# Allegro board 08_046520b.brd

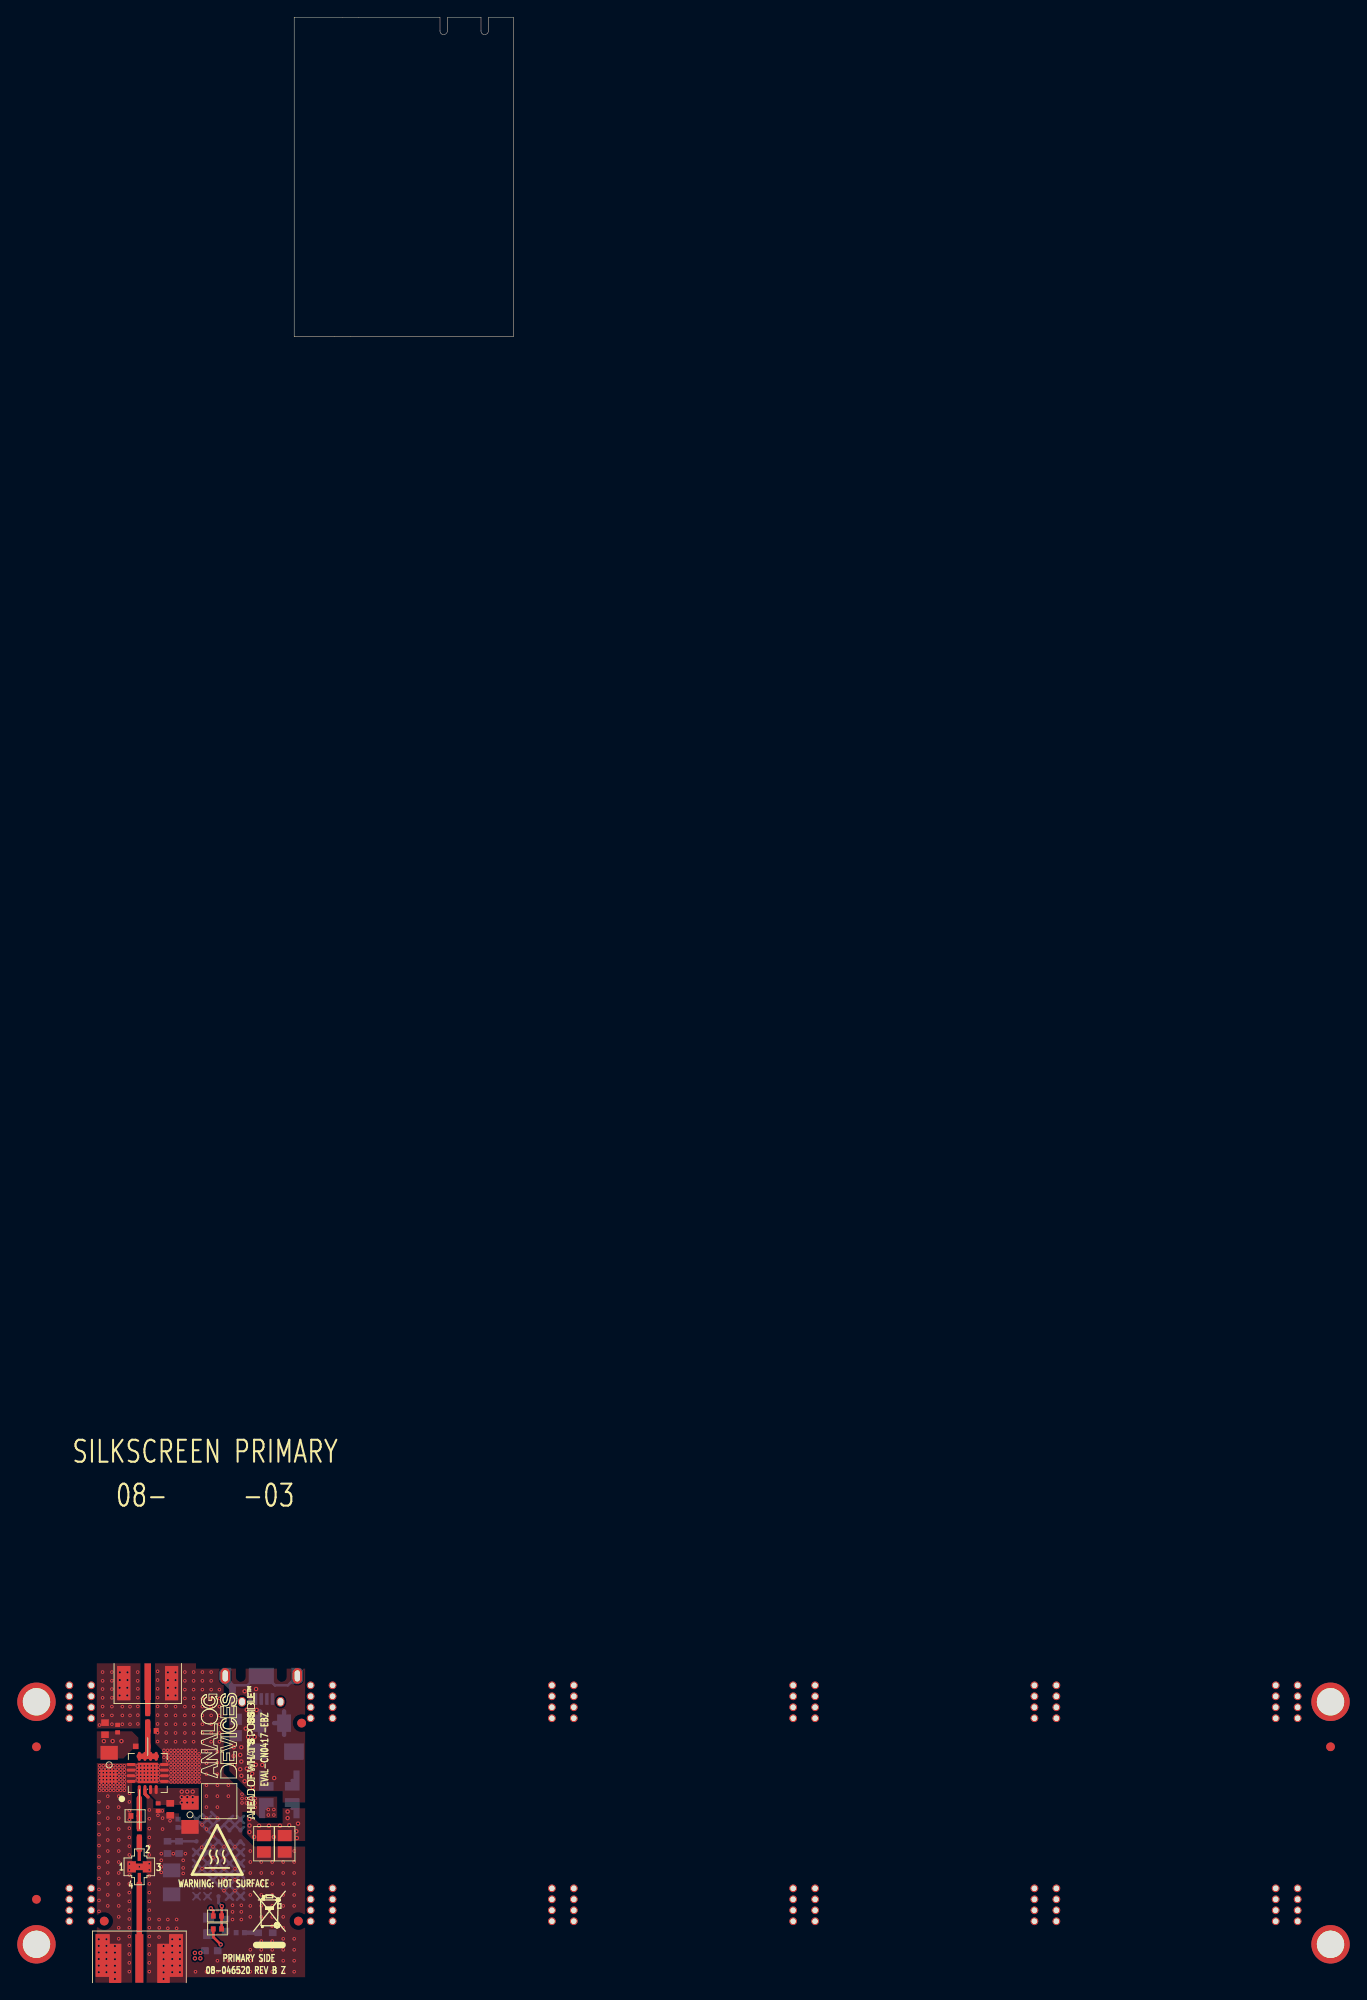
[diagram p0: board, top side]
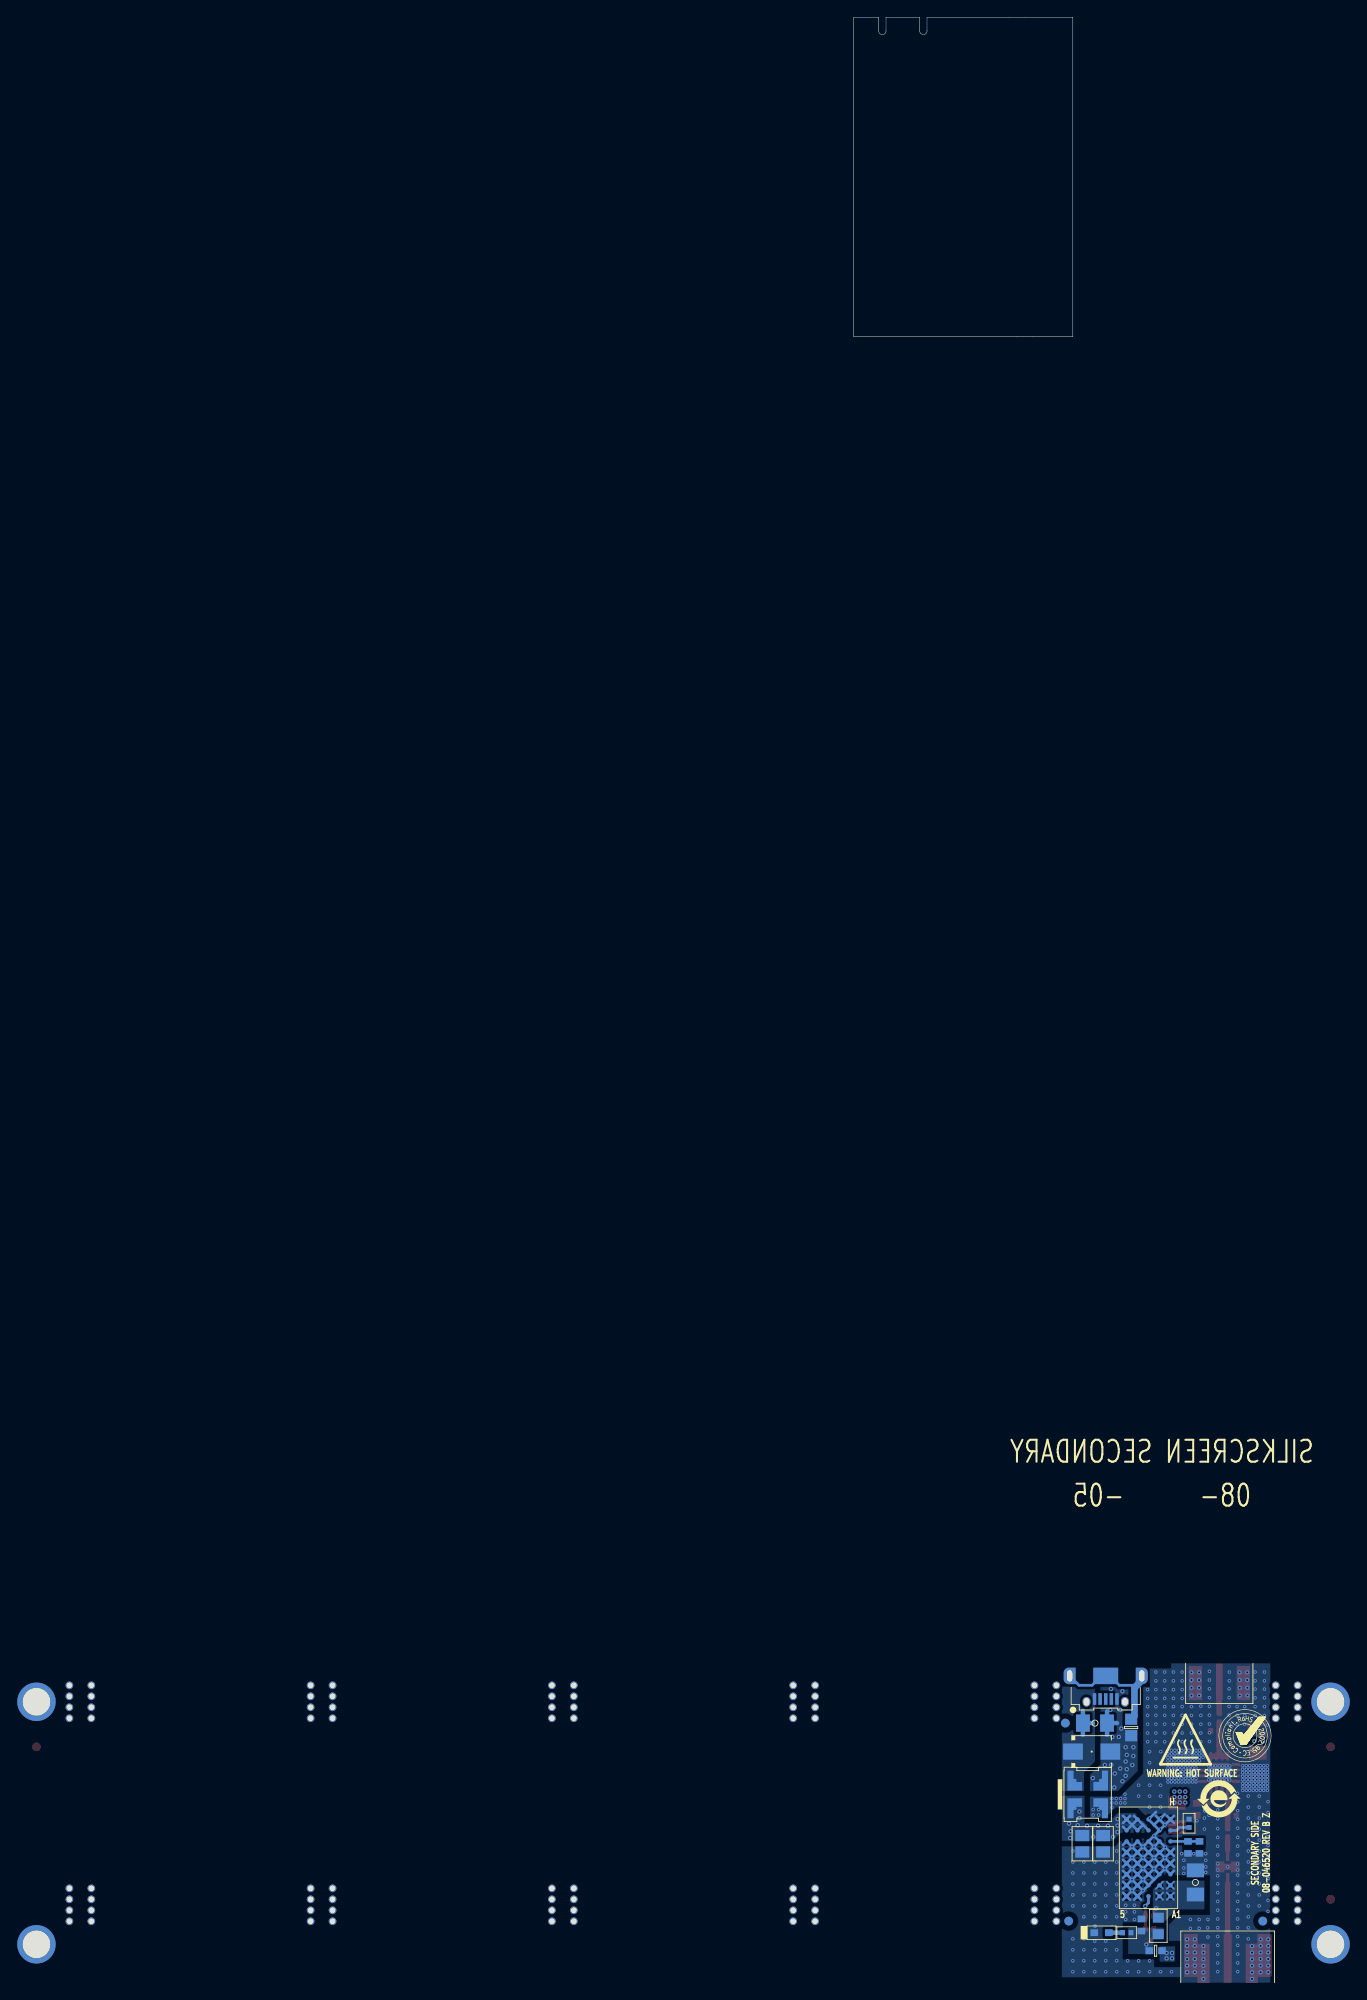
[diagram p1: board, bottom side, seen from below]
Outline 25.4 x 36.96 mm; copper layers: TOP, L2_GND, L3_PWR, BOTTOM. Coordinates in mm from the lower left corner of the outline.
Outline path: 0,36.96 16.88,36.96 16.88,35.38 arc(17.31,34.96) 17.74,35.38 17.74,36.96 21.63,36.96 21.63,35.38 arc(22.06,34.96) 22.49,35.38 22.49,36.96 25.4,36.96 25.4,0 0,0 0,36.96

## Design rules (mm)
constraint set DEFAULT: min track width 0.203
net group AMP: nets UNNAMED_7_ADL5606_I18_RFIN UNNAMED_7_ADL5606_I18_RFOUT1 UNNAMED_7_CAP_I75_N1 UNNAMED_7_CAP_I76_N2 UNNAMED_7_CNBNC5P_I149_CNTR UNNAMED_7_LINLTM8045_I104_FB

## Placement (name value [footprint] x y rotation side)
A1  ADL5606ACPZ  [QFN16_4X4_PAD2_36X2_36]  -16.96 -166.22 0 top
C1  20PF  [C0402#2]  -17.93 -173.16 90 top
C2  47UF  [C1206H71]  -2.57 -160.45 0 bottom
C3  4.7UF  [C0805H53]  -1.09 -174.42 90 bottom
C4  0.1UF  [C0805H53]  -3.51 -174.42 90 top
C5  0.1UF  [C0805H53]  -1.09 -174.42 90 top
C6  1UF  [C0603]  -13.33 -174.84 90 bottom
C7  0.1UF  [C0805H53]  -3.51 -174.42 90 bottom
C8  20PF  [C0402#2]  -16.96 -159.85 90 top
C9  1UF  [C0603]  -14.67 -174.84 90 bottom
C10  10UF  [C1206H71]  -12.06 -171.07 270 top
C11  0.01UF  [C0603]  -14.35 -170.43 270 top
C12  100pF  [C0402#2]  -15.75 -170.18 270 top
C13  10UF  [C1206H71]  -21.42 -165.29 270 top
C14  0.01UF  [C0603]  -21.91 -161.1 90 top
C15  100pF  [C0402#2]  -20.45 -161.1 90 top
C16  100uF  [C1206H71]  -14.2 -178.89 270 bottom
C17  1UF  [C0603]  -7.95 -183.82 270 bottom
CIN  2pF  [C0402]  -18.42 -171.2 0 top
COUT  3.3PF  [C0402]  -16.47 -161.35 180 top
D1  SMAJ5.0A-13-F  [DIOSMJ5_0]  -2.18 -163.76 180 bottom
DS1  LTST-C191KGKT  [LED0603_A]  -3.33 -184.71 180 bottom
E1  600OHM AT 100MEGHZ  [L0603]  -9.59 -186.8 180 bottom
FL1  2400-2500MEGHZ  [FL0805_A]  -17.93 -177.09 270 top
J1  132365-10  [CNSMARAL686W375H177]  -17.93 -190.5 270 top
J2  CON-SMA-EDGE-S  [CNSMARAL525W250H148]  -16.96 -153.54 90 top
L1  800OHMS AT 100MEGHZ  [L2020_A]  -1.73 -168.71 270 bottom
L2  18NH  [L7144A]  -17.66 -163.14 180 top
L3  1uH  [L0805]  -9.91 -183.92 270 bottom
NOREF  -  []  16.88 36.96 0 top
NOREF#2  -  []  21.63 36.96 0 top
NOREF#3  -  [unnamed#2]  57.78 -180.85 0 top
NOREF#4  -  [unnamed#2]  1.91 -179.58 0 top
NOREF#5  -  [unnamed#2]  1.91 -182.12 0 top
NOREF#6  -  [unnamed#2]  85.72 -156.08 0 top
NOREF#7  -  [unnamed#2]  -26.04 -156.08 0 top
NOREF#8  -  [unnamed#2]  29.84 -158.62 0 top
NOREF#9  -  [unnamed#2]  -23.49 -158.62 0 top
NOREF#10  -  []  22.49 36.96 0 top
NOREF#11  -  [unnamed#2]  32.38 -159.89 0 top
NOREF#12  -  [unnamed#2]  113.67 -180.85 0 top
NOREF#13  -  [unnamed#2]  116.2 -156.08 0 top
NOREF#14  -  []  177 11.95 0 top
NOREF#15  -  [unnamed#2]  85.72 -183.39 0 top
NOREF#16  -  [unnamed#2]  60.33 -182.12 0 top
NOREF#17  -  [unnamed#2]  57.78 -157.35 0 top
NOREF#18  -  [unnamed#2]  1.91 -159.89 0 top
NOREF#19  -  []  32.38 -190.5 0 top
NOREF#20  -  [unnamed#2]  116.2 -179.58 0 top
NOREF#21  -  []  -23.49 -190.5 0 top
NOREF#22  -  [unnamed#2]  88.27 -157.35 0 top
NOREF#23  -  [unnamed#2]  60.33 -179.58 0 top
NOREF#24  -  [unnamed#2]  85.72 -180.85 0 top
NOREF#25  -  [unnamed#2]  -29.84 -157.99 0 top
NOREF#26  -  [unnamed#2]  57.78 -159.89 0 top
NOREF#27  -  []  0 0 0 top
NOREF#28  -  [unnamed#2]  -29.84 -180.85 0 top
NOREF#29  -  [unnamed#2]  113.67 -158.62 0 top
NOREF#30  -  [unnamed#2]  -29.84 -186.06 0 top
NOREF#31  -  []  88.27 -190.5 0 top
NOREF#32  -  [unnamed#2]  60.33 -156.08 0 top
NOREF#33  -  []  85.72 -190.5 0 top
NOREF#34  -  [unnamed#2]  32.38 -183.39 0 top
NOREF#35  -  [unnamed#2]  85.72 -158.62 0 top
NOREF#36  -  [unnamed#2]  4.45 -158.62 0 top
NOREF#37  -  []  25.4 0 0 top
NOREF#38  -  [unnamed#2]  -23.49 -156.08 0 top
NOREF#39  -  []  -3.07 -186.45 0 top
NOREF#40  -  [unnamed#2]  88.27 -159.89 0 top
NOREF#41  -  [unnamed#2]  88.27 -158.62 0 top
NOREF#42  -  [unnamed#2]  0.48 -183.37 0 top
NOREF#43  -  [unnamed#2]  4.45 -179.58 0 top
NOREF#44  -  []  -33.66 -190.5 0 top
NOREF#45  -  [unnamed#2]  1.91 -157.35 0 top
NOREF#46  -  [unnamed#2]  120.02 -186.06 0 top
NOREF#47  -  [unnamed#2]  32.38 -180.85 0 top
NOREF#48  -  []  29.84 -190.5 0 top
NOREF#49  -  [unnamed#2]  -26.04 -182.12 0 top
NOREF#50  -  [unnamed#2]  85.72 -182.12 0 top
NOREF#51  -  []  1.5 7.13 0 top
NOREF#52  -  [unnamed#2]  113.67 -179.58 0 top
NOREF#53  -  [unnamed#2]  29.84 -182.12 0 top
NOREF#54  -  []  -108.74 -271.92 0 top
NOREF#55  -  []  -29.84 -186.06 0 top
NOREF#56  -  [unnamed#2]  60.33 -180.85 0 top
NOREF#57  -  []  -29.84 -186.06 0 top
NOREF#58  -  []  183.04 23.81 90 top
NOREF#59  -  []  9.05 -48.78 0 top
NOREF#60  -  [unnamed#2]  32.38 -182.12 0 top
NOREF#61  -  []  4.45 -190.5 0 top
NOREF#62  -  []  0 0 0 top
NOREF#63  -  []  1.91 -190.5 0 top
NOREF#64  -  []  113.67 -190.5 0 top
NOREF#65  -  [unnamed#2]  60.33 -157.35 0 top
NOREF#66  -  []  -5.08 -153.54 180 top
NOREF#67  -  [unnamed#2]  -26.04 -180.85 0 top
NOREF#68  -  [unnamed#2]  88.27 -180.85 0 top
NOREF#69  -  []  -33.66 -153.54 0 top
NOREF#70  -  []  116.2 -190.5 0 top
NOREF#71  -  []  16.47 33.39 0 top
NOREF#72  -  []  17.74 36.96 0 top
NOREF#73  -  [unnamed#2]  1.91 -158.62 0 top
NOREF#74  -  [unnamed#2]  88.27 -182.12 0 top
NOREF#75  -  [unnamed#2]  29.84 -159.89 0 top
NOREF#76  -  []  123.83 -190.5 0 top
NOREF#77  -  [unnamed#2]  4.45 -157.35 0 top
NOREF#78  -  [unnamed#2]  120.02 -157.99 0 top
NOREF#79  -  [unnamed#2]  1.91 -183.39 0 top
NOREF#80  -  [unnamed#2]  0.86 -160.45 0 top
NOREF#81  -  []  -27.23 -100.31 0 top
NOREF#82  -  []  187.79 -7.49 0 top
NOREF#83  -  [unnamed#2]  -26.04 -157.35 0 top
NOREF#84  -  [unnamed#2]  60.33 -183.39 0 top
NOREF#85  -  [unnamed#2]  113.67 -159.89 0 top
NOREF#86  -  [unnamed#2]  116.2 -180.85 0 top
NOREF#87  -  [unnamed#2]  57.78 -158.62 0 top
NOREF#88  -  [unnamed#2]  4.45 -180.85 0 top
NOREF#89  -  []  0 36.96 0 top
NOREF#90  -  []  177 26.12 0 top
NOREF#91  -  []  25.4 0 90 top
NOREF#92  -  [unnamed#2]  -23.49 -157.35 0 top
NOREF#93  -  [unnamed#2]  85.72 -157.35 0 top
NOREF#94  -  [unnamed#2]  57.78 -179.58 0 top
NOREF#95  -  []  165.98 23.84 0 top
NOREF#96  -  [unnamed#2]  88.27 -156.08 0 top
NOREF#97  -  [unnamed#2]  1.91 -156.08 0 top
NOREF#98  -  []  -108.74 -271.92 0 top
NOREF#99  -  [unnamed#2]  -23.49 -179.58 0 top
NOREF#100  -  []  -23.49 -190.5 0 top
NOREF#101  -  []  -33.66 -190.5 0 top
NOREF#102  -  [unnamed#2]  -23.49 -183.39 0 top
NOREF#103  -  [unnamed#2]  4.45 -156.08 0 top
NOREF#104  -  [unnamed#2]  32.38 -158.62 0 top
NOREF#105  -  [unnamed#2]  -26.04 -158.62 0 top
NOREF#106  -  [unnamed#2]  -26.04 -159.89 0 top
NOREF#107  -  [unnamed#2]  4.45 -159.89 0 top
NOREF#108  -  []  -92.88 125.68 0 top
NOREF#109  -  [unnamed#2]  29.84 -157.35 0 top
NOREF#110  -  []  57.78 -190.5 0 top
NOREF#111  -  [unnamed#2]  116.2 -157.35 0 top
NOREF#112  -  [unnamed#2]  32.38 -157.35 0 top
NOREF#113  -  [unnamed#2]  -22 -183.37 0 top
NOREF#114  -  []  174.64 -5.83 90 top
NOREF#115  -  [unnamed#2]  4.45 -182.12 0 top
NOREF#116  -  [unnamed#2]  116.2 -159.89 0 top
NOREF#117  -  [unnamed#2]  57.78 -183.39 0 top
NOREF#118  -  []  -50 17.88 0 top
NOREF#119  -  [unnamed#2]  88.27 -179.58 0 top
NOREF#120  -  [unnamed#2]  32.38 -156.08 0 top
NOREF#121  -  [unnamed#2]  85.72 -179.58 0 top
NOREF#122  -  []  28.1 -44.97 0 top
NOREF#123  -  []  0 36.96 0 top
NOREF#124  -  [unnamed#2]  1.91 -180.85 0 top
NOREF#125  -  [unnamed#2]  113.67 -182.12 0 top
NOREF#126  -  [unnamed#2]  4.45 -183.39 0 top
NOREF#127  -  [unnamed#2]  60.33 -159.89 0 top
NOREF#128  -  []  -26.04 -190.5 0 top
NOREF#129  -  [unnamed#2]  113.67 -157.35 0 top
NOREF#130  -  [unnamed#2]  29.84 -179.58 0 top
NOREF#131  -  [unnamed#2]  29.84 -156.08 0 top
NOREF#132  -  []  -23.49 -153.54 270 top
NOREF#133  -  []  171.17 -76.31 0 top
NOREF#134  -  [unnamed#2]  -23.49 -159.89 0 top
NOREF#135  -  []  179.36 29.73 90 top
NOREF#136  -  [unnamed#2]  29.84 -180.85 0 top
NOREF#137  -  []  -22.27 -162.95 0 top
NOREF#138  -  [unnamed#2]  60.33 -158.62 0 top
NOREF#139  -  [unnamed#2]  85.72 -159.89 0 top
NOREF#140  -  [unnamed#2]  -23.49 -182.12 0 top
NOREF#141  -  [unnamed#2]  57.78 -182.12 0 top
NOREF#142  -  [unnamed#2]  116.2 -182.12 0 top
NOREF#143  -  []  -108.74 -271.92 0 top
NOREF#144  -  [unnamed#2]  -26.04 -179.58 0 top
NOREF#145  -  []  60.33 -190.5 0 top
NOREF#146  -  [unnamed#2]  116.2 -158.62 0 top
NOREF#147  -  [unnamed#2]  29.84 -183.39 0 top
NOREF#148  -  [unnamed#2]  32.38 -179.58 0 top
NOREF#149  -  [unnamed#2]  -23.49 -180.85 0 top
NOREF#150  -  [unnamed#2]  116.2 -183.39 0 top
NOREF#151  -  [unnamed#2]  120.02 -163.19 0 top
NOREF#152  -  []  1.5 7.13 0 top
NOREF#153  -  [unnamed#2]  -29.84 -163.19 0 top
NOREF#154  -  []  -5.08 -190.5 90 top
NOREF#155  -  [unnamed#2]  113.67 -156.08 0 top
NOREF#156  -  [unnamed#2]  -26.04 -183.39 0 top
NOREF#157  -  []  165.98 -16.72 0 top
NOREF#158  -  []  -10.31 -135.27 0 top
NOREF#159  -  [unnamed#2]  113.67 -183.39 0 top
NOREF#160  -  [unnamed#2]  57.78 -156.08 0 top
NOREF#161  -  [unnamed#2]  88.27 -183.39 0 top
NOREF#162  -  [unnamed#2]  0.86 -160.45 180 bottom
NOREF#163  -  [unnamed#2]  -22 -183.37 180 bottom
NOREF#164  -  [unnamed#2]  0.48 -183.37 180 bottom
NOREF#165  -  []  -16.92 -169.22 180 bottom
P1  47590-0001  [CNMOLEX47590-0001]  -3.81 -153.54 270 bottom
R1  1K  [R0805]  -6.76 -160.96 90 bottom
R2  60.4K  [R0402]  -8.89 -182.78 180 top
R3  182K  [R0402]  -8.89 -184.28 180 top
R4  140  [R0402]  -6.25 -184.71 180 bottom
RT  115K  [R0402]  -13.46 -172.05 90 bottom
U1  LTM8045MPY#PBF  [BGA40]  -8.76 -176.05 90 bottom

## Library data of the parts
A1 = ADL5606: User Part Number: UPN; Tolerance: N/A; alternate symbols: (); part number: ADL5606_SM-ADL5606ACPZ,E026828,QFN16_4X4_PAD2_36X2_36; tolerance: N/A
C1 C8 = CAP: Tolerance: 5; User Part Number: UPN; alternate symbols: C0402L_ALT; part number: CAP_SM-20PF,50V,5,E033239,C0402; tolerance: 5
C2 = CAP: Tolerance: 20; User Part Number: UPN; alternate symbols: (); part number: CAP_SM-47UF,10V,20,E028092,C1206H71; tolerance: 20
C3 = CAP: Tolerance: 10; User Part Number: UPN; alternate symbols: (); part number: CAP_SM-4.7UF,25V,10,E025752,C0805H53; tolerance: 10
C4 C5 C7 = CAP: Tolerance: 10; User Part Number: UPN; alternate symbols: (); part number: CAP_SM-0.1UF,50V,10,E033336,C0805H53; tolerance: 10
C6 C9 C17 = CAP: Tolerance: 10; User Part Number: UPN; alternate symbols: C0603L_ALT; part number: CAP_SM-1UF,25V,10,E025743,C0603; tolerance: 10
C10 C13 = CAP: Tolerance: 10; User Part Number: UPN; alternate symbols: (); part number: CAP_SM-10UF,10V,10,E027443,C1206H71; tolerance: 10
C11 C14 = CAP: Tolerance: 10; User Part Number: UPN; alternate symbols: C0603L_ALT; part number: CAP_SM-0.01UF,100V,10,E032297,C0603; tolerance: 10
C12 C15 = CAP: Tolerance: 5; User Part Number: UPN; alternate symbols: C0402L_ALT; part number: CAP_SM-100PF,50V,5,E022402,C0402; tolerance: 5
C16 = CAP: Tolerance: 20; User Part Number: UPN; alternate symbols: (); part number: CAP_SM-100UF,6.3V,20,E016591,C1206H71; tolerance: 20
CIN = CAP: Tolerance: 0.25pF; User Part Number: UPN; alternate symbols: C0402L_ALT; part number: CAP_SM-2PF,50V,0.25PF,E012548,C0402; tolerance: 0.25pF
COUT = CAP: Tolerance: 0.1PF; User Part Number: UPN; alternate symbols: C0402L_ALT; part number: CAP_SM-3.3PF,50V,0.1PF,E027135,C0402; tolerance: 0.1PF
D1 = DIO: Tolerance: N/A; User Part Number: UPN; alternate symbols: (); part number: DIO_SM-SMAJ5.0A-13-F,5V,N/A,E001108,DIOSMJ5_0; tolerance: N/A
DS1 = DIOLED: User Part Number: UPN; Tolerance: N/A; alternate symbols: (); part number: DIOLED_SM-LTST-C191KGKT,2V,N/A,E033001,LED0603_A; tolerance: N/A
E1 = FERRITE: Tolerance: 25; User Part Number: UPN; alternate symbols: (); part number: FERRITE_SM-600OHM AT 100MEGHZ,25,E028908,L0603; tolerance: 25
FL1 = FLTRBP4P_V2: User Part Number: UPN; Tolerance: N/A; alternate symbols: (); part number: FLTRBP4P_V2_SM-2400-2500MEGHZ,E023131,FL0805_A; tolerance: N/A
J1 = CNBNC5P: alternate symbols: (CNSMARAL686W375H177_CNSMARAL535W256H152); part number: CNBNC5P_SM-132365-10,E033180,CNSMARAL686W375H177; tolerance: N/A
J2 = CNBNC5P: Tolerance: N/A; User Part Number: UPN; alternate symbols: (); part number: CNBNC5P_SM-CON-SMA-EDGE-S,E028678,CNSMARAL525W250H148; tolerance: N/A
L1 = CHOKE4P: User Part Number: UPN; Tolerance: N/A; alternate symbols: (); part number: CHOKE4P_SM-800OHMS AT 100MEGHZ,N/A,E027130,L2020_A; tolerance: N/A
L2 = IND: Tolerance: 5; User Part Number: UPN; alternate symbols: (); part number: IND_SM-18NH,5,E029275,L7144A; tolerance: 5
L3 = IND: Tolerance: 20; User Part Number: UPN; alternate symbols: (L0805L); part number: IND_SM-1UH,20,E010399,L0805; tolerance: 20
P1 = CN5P_3SHLD: User Part Number: UPN; Tolerance: N/A; alternate symbols: (); part number: CN5P_3SHLD_SM-47590-0001,E015753,CNMOLEX47590-0001; tolerance: N/A
R1 = RES: Tolerance: 1; User Part Number: UPN; alternate symbols: (R0805L); part number: RES_SM-1K,E023448,1/3W,1,R0805; tolerance: 1
R2 = RES: Tolerance: 1; User Part Number: UPN; alternate symbols: (R0402L); part number: RES_SM-60.4K,E022436,1/10W,1,R0402; tolerance: 1
R3 = RES: Tolerance: 1; User Part Number: UPN; alternate symbols: (R0402L); part number: RES_SM-182K,E025180,1/10W,1,R0402; tolerance: 1
R4 = RES: Tolerance: 1; User Part Number: UPN; alternate symbols: (R0402L); part number: RES_SM-140,E006740,1/16W,1,R0402; tolerance: 1
RT = RES: Tolerance: 1; User Part Number: UPN; alternate symbols: (R0402L); part number: RES_SM-115K,E025179,1/10W,1,R0402; tolerance: 1
U1 = LINLTM8045: Tolerance: N/A; User Part Number: UPN; alternate symbols: (); part number: LINLTM8045_SM-LTM8045MPY#PBF,E028897,BGA40; tolerance: N/A

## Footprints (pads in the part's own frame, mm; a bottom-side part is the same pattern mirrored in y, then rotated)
BGA40
  round 0.508 smd: A1(-4.445,-2.54) A2(-4.445,-1.27) A3(-4.445,0) A4(-4.445,1.27) A5(-4.445,2.54) B1(-3.175,-2.54) B2(-3.175,-1.27) B3(-3.175,0) B4(-3.175,1.27) B5(-3.175,2.54) C1(-1.905,-2.54) C2(-1.905,-1.27) C3(-1.905,0) C4(-1.905,1.27) C5(-1.905,2.54) D1(-0.635,-2.54) D2(-0.635,-1.27) D3(-0.635,0) D4(-0.635,1.27) D5(-0.635,2.54) E1(0.635,-2.54) E2(0.635,-1.27) E3(0.635,0) E4(0.635,1.27) E5(0.635,2.54) F1(1.905,-2.54) F2(1.905,-1.27) F3(1.905,0) F4(1.905,1.27) F5(1.905,2.54) G1(3.175,-2.54) G2(3.175,-1.27) G3(3.175,0) G4(3.175,1.27) G5(3.175,2.54) H1(4.445,-2.54) H2(4.445,-1.27) H3(4.445,0) H4(4.445,1.27) H5(4.445,2.54)
C0402
  rect 0.584x0.66 smd: 1(-0.49,0) 2(0.49,0)
C0402#2
  rect 0.483x0.559 smd: 1(-0.438,0) 2(0.438,0)
C0603
  rect 0.762x0.889 smd: 1(-0.699,0) 2(0.699,0)
C0805H53
  rect 1.295x1.6 smd: 1(-0.953,0) 2(0.953,0)
C1206H71
  rect 1.6x2.007 smd: 1(-1.397,0) 2(1.397,0)
CNMOLEX47590-0001
  oval 1.118x0.914 hole 0.864x0.66: (4.45,-2.225) (4.45,2.225)
  rect 1.346x0.406 smd: 1(4.123,-1.3) 2(4.123,-0.65) 3(4.123,0) 4(4.123,0.65) 5(4.123,1.3)
  oval 1.803x1.118 hole 1.295x0.61: SH1(1.45,4.175) SH3(1.45,-4.175)
  rect 1.905x2.896 smd: SH2(1.45,0)
CNSMARAL525W250H148
  rect 4.242x0.762 smd: 1(-2.121,0)
  rect 3.962x1.499 smd: 2(-2.281,2.77) 3(-2.281,2.77) 4(-2.281,-2.77) 5(-2.281,-2.77)
CNSMARAL686W375H177
  rect 5.613x0.94 smd: 1(-2.807,0)
  custom 0.737x0.737 smd: 2(-2.801,3.576) 3(-2.801,-3.576) 4(-2.801,3.576) 5(-2.801,-3.576)
DIOSMJ5_0
  rect 2.286x1.88 smd: A(2.164,0) C(-2.164,0)
FL0805_A
  rect 1.295x0.991 smd: 1(0,-0.895) 3(0,0.895)
  rect 0.991x0.356 smd: 2(-1.195,0) 4(1.195,0)
L0603
  rect 0.889x0.813 smd: 1(-0.737,0) 2(0.737,0)
L0805
  rect 1.143x1.27 smd: 1(-0.953,0) 2(0.953,0)
L2020_A
  custom 0.425x0.425 smd: 1(-1.606,-1.501) 2(1.606,-1.501) 3(1.606,1.501) 4(-1.606,1.501)
L7144A
  rect 0.635x0.635 smd: 1(-0.699,0) 2(0.699,0)
LED0603_A
  rect 0.889x0.787 smd: A(0.845,0) C(-0.845,0)
QFN16_4X4_PAD2_36X2_36
  oval 0.356x1.041 smd: 1(-0.975,-1.925) 2(-0.325,-1.925) 3(0.325,-1.925) 4(0.975,-1.925) 9(0.975,1.925) 10(0.325,1.925) 11(-0.325,1.925) 12(-0.975,1.925)
  oval 1.041x0.356 smd: 5(1.925,-0.975) 6(1.925,-0.325) 7(1.925,0.325) 8(1.925,0.975) 13(-1.925,0.975) 14(-1.925,0.325) 15(-1.925,-0.325) 16(-1.925,-0.975)
  rect 2.362x2.362 smd: PAD(0,0)
R0402
  rect 0.559x0.61 smd: 1(-0.483,0) 2(0.483,0)
R0805
  rect 1.295x1.397 smd: 1(-0.953,0) 2(0.953,0)
unnamed#2
  round 0.889 hole 0.635 unplated: (0,0)

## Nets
5V: A1.3(VCC) A1.4 C10.1 C11.1 C12.1 C13.1 C14.1 C15.1 E1.2(N2) L2.2(N2)
GND: A1.2 A1.5 A1.6 A1.7 A1.8 A1.13 A1.14 A1.15 A1.16 A1.PAD C3.1 C4.1 C5.1 C6.1 C7.1 C9.1 C10.2(N2) C11.2(N2) C12.2(N2) C13.2(N2) C14.2(N2) C15.2(N2) C16.1 C17.1 CIN.1 COUT.1 DS1.C FL1.1 FL1.3 J1.2 J1.3 J1.4 J1.5(SH4) J2.2 J2.3 J2.4 J2.5(SH4) L1.3 RT.2(N2) U1.A4 U1.A5 U1.B3 U1.B4 U1.B5(VOUT-_4) U1.C1 U1.C2 U1.C3 U1.C4 U1.C5 U1.D1 U1.D2 U1.D3 U1.D4 U1.D5 U1.E1 U1.E2 U1.E3 U1.E4 U1.E5 U1.F2 U1.F3 U1.F4 U1.F5 U1.G2 U1.H1 U1.H2 U1.H3
PGND: C2.1 D1.A(P) L1.4(N4) P1.5 R1.1
UNNAMED_7_ADL5606_I18_RFIN: A1.1 C1.2(N2) CIN.2(N2)
UNNAMED_7_ADL5606_I18_RFOUT1: A1.9 A1.10 A1.11 A1.12 C8.1 COUT.2(N2) L2.1
UNNAMED_7_CAP_I75_N1: C1.1 FL1.2(OUT)
UNNAMED_7_CAP_I76_N2: C8.2(N2) J2.1
UNNAMED_7_CAP_I108_N2: C16.2(N2) L3.1 R2.2(N2) U1.A1 U1.A2 U1.B1 U1.B2
UNNAMED_7_CAP_I113_N2: C3.2(N2) C4.2(N2) C5.2(N2) C7.2(N2) L1.2 U1.G3 U1.G4 U1.G5 U1.H4 U1.H5
UNNAMED_7_CAP_I120_N2: C2.2(N2) D1.C L1.1 P1.1
UNNAMED_7_CAP_I132_N2: C6.2(N2) C9.2(N2) U1.F1
UNNAMED_7_CN5P3SHLD_I127_N6: P1.SH1 P1.SH2 P1.SH3(N8) R1.2(N2)
UNNAMED_7_CNBNC5P_I149_CNTR: FL1.4 J1.1
UNNAMED_7_DIOLED_I150_P: DS1.A(P) R4.1
UNNAMED_7_FERRITE_I107_N1: C17.2(N2) E1.1 L3.2(N2) R3.2(N2) R4.2(N2)
UNNAMED_7_LINLTM8045_I104_FB: R2.1 R3.1 U1.A3
UNNAMED_7_LINLTM8045_I104_RT: RT.1 U1.G1

Pads without a net: P1 2 3 4

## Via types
v1: diameter 0.508, hole 0.254, TOP to BOTTOM, 107 vias
v2: diameter 0.406, hole 0.203, TOP to BOTTOM, 499 vias

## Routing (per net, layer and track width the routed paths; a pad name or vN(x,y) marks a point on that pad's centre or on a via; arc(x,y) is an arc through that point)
5V:
  vias: v1(-22.04,-162.54) v1(-21.02,-162.54) v1(-20.01,-162.54) v1(-13.02,-168.38) v1(-13.02,-169.02) v1(-13.02,-169.65) v1(-12.39,-168.38) v1(-12.39,-169.02) v1(-12.39,-169.65) v1(-11.75,-168.38) v1(-11.75,-169.02) v1(-11.75,-169.65) v1(-11.5,-187.05) v1(-11.5,-187.69) v1(-10.86,-187.05) v1(-10.86,-187.69)
GND: length 82.9
  TOP w0.356: A1.2 -17.28,-168.65 -17.24,-168.69
  TOP w0.381: -16.92,-169.02 -17.24,-168.69
  BOTTOM w0.305: U1.H2 -10.64,-171 ; U1.H2 -9.4,-172.24 ; U1.H2 v2(-10.67,-172.24) ; U1.H2 -9.62,-171.19 ; U1.A4 v2(-8.13,-179.86) ; U1.A4 v2(-6.86,-179.86) ; U1.A4 -7.08,-180.9 ; U1.A4 -7.9,-180.9 ; v2(-8.13,-179.86) U1.B3 ; v2(-8.13,-179.86) U1.B4 ; v2(-8.13,-178.59) U1.C4 ; v2(-8.13,-178.59) U1.B3 ; v2(-8.13,-178.59) U1.B4 ; v2(-8.13,-178.59) U1.C3 ; U1.C4 v2(-6.86,-177.32) ; U1.C4 v2(-8.13,-177.32) ; U1.C4 v2(-6.86,-178.59) ; U1.D1 -11.71,-176.27 ; U1.D1 v2(-10.67,-177.32) ; U1.D1 v2(-10.67,-176.05) ; U1.D1 -11.71,-177.09 ; -11.71,-177.54 U1.C1 v2(-10.67,-177.32) ; v2(-9.4,-174.78) U1.E3 ; v2(-9.4,-174.78) U1.E2 ; v2(-9.4,-174.78) U1.F3 ; v2(-9.4,-174.78) U1.F2 ; U1.E3 v2(-8.13,-174.78) ; U1.E3 v2(-8.13,-176.05) ; U1.E3 v2(-9.4,-176.05) ; U1.B5 -5.81,-179.63 ; U1.B5 -5.81,-178.81 ; U1.B5 v2(-6.86,-179.86) ; U1.B5 v2(-6.86,-178.59) ; U1.D3 v2(-9.4,-177.32) ; U1.D3 v2(-9.4,-176.05) ; U1.D3 v2(-8.13,-176.05) ; U1.D3 v2(-8.13,-177.32) ; v2(-9.4,-177.32) U1.C2 ; v2(-9.4,-177.32) U1.D2 ; v2(-9.4,-177.32) U1.C3 ; U1.E5 v2(-6.86,-174.78) ; U1.E5 -5.81,-175 ; U1.E5 v2(-6.86,-176.05) ; U1.E5 -5.81,-175.82 ; v2(-6.86,-174.78) U1.F5 -5.81,-174.55 ; v2(-6.86,-174.78) U1.E4 ; v2(-6.86,-174.78) U1.F4 v2(-8.13,-174.78) ; U1.D4 v2(-8.13,-177.32) ; U1.D4 v2(-6.86,-177.32) ; U1.D4 v2(-8.13,-176.05) ; U1.D4 v2(-6.86,-176.05) ; v2(-8.13,-177.32) U1.C3 ; U1.C2 v2(-10.67,-177.32) ; U1.C2 -9.4,-178.59 ; v2(-9.4,-176.05) U1.E2 ; v2(-9.4,-176.05) U1.D2 ; U1.E2 -10.11,-175.41 v2(-10.71,-174.82) ; U1.E2 v2(-10.67,-176.05) ; v2(-6.86,-177.32) U1.C5 ; v2(-6.86,-177.32) U1.D5 ; v2(-8.13,-174.78) U1.F3 ; v2(-8.13,-174.78) U1.E4 ; U1.F3 v2(-9.4,-173.51) ; U1.H1 -11.71,-171.19 ; U1.H1 -11.71,-172.01 ; U1.H1 v2(-10.67,-172.24) ; U1.H1 -10.89,-171.19 ; v2(-10.71,-174.82) U1.F2 ; v2(-10.71,-174.82) U1.E1 ; U1.F2 v2(-9.4,-173.51) ; U1.G2 -9.4,-172.24 ; U1.G2 v2(-10.67,-172.24) ; U1.G2 v2(-9.4,-173.51) ; -9.4,-172.24 U1.H3 -9.62,-170.74 ; U1.B3 -9.4,-178.59 ; v2(-6.86,-178.59) U1.C5 ; v2(-6.86,-178.59) U1.B4 ; U1.C5 -5.81,-178.36 ; U1.C5 -5.81,-177.54 ; U1.B4 v2(-6.86,-179.86) ; v2(-6.86,-179.86) U1.A5 ; -6.63,-180.9 U1.A5 ; U1.A5 -5.81,-180.9 ; U1.A5 -5.81,-180.08 ; U1.C3 -9.4,-178.59 ; v2(-10.67,-177.32) U1.D2 ; U1.D2 v2(-10.67,-176.05) ; v2(-6.86,-176.05) U1.D5 ; v2(-6.86,-176.05) U1.E4 ; U1.D5 -5.81,-177.09 ; U1.D5 -5.81,-176.27 ; U1.E1 v2(-10.67,-176.05) ; U1.E1 -11.71,-175 ; U1.E1 -11.71,-175.82 ; v2(-8.13,-176.05) U1.E4
  vias: v1(-22.63,-185.47) v1(-22.63,-186.24) v1(-22.63,-187) v1(-22.63,-187.76) v1(-22.63,-188.52) v1(-22.63,-189.28) v1(-21.74,-185.47) v1(-21.74,-186.24) v1(-21.74,-187) v1(-21.74,-187.76) v1(-21.74,-188.52) v1(-21.74,-189.28) v1(-20.76,-186.26) v1(-20.76,-187.02) v1(-20.76,-187.78) v1(-20.76,-188.54) v1(-20.76,-189.3) v1(-20.76,-190.07) v1(-20.19,-154.58) v1(-20.19,-155.47) v1(-20.22,-156.37) v1(-20.22,-157.26) v1(-19.3,-154.58) v1(-19.3,-155.47) v1(-19.33,-156.37) v1(-19.33,-157.26) v1(-15.13,-186.26) v1(-15.13,-187.02) v1(-15.13,-187.78) v1(-15.13,-188.54) v1(-15.13,-189.3) v1(-15.13,-190.07) v1(-14.63,-154.59) v1(-14.63,-155.48) v1(-14.63,-156.37) v1(-14.63,-157.26) v1(-14.12,-185.47) v1(-14.12,-186.24) v1(-14.12,-187) v1(-14.12,-187.76) v1(-14.12,-188.52) v1(-14.12,-189.28) v1(-13.74,-154.59) v1(-13.74,-155.48) v1(-13.74,-156.37) v1(-13.74,-157.26) v1(-13.23,-185.47) v1(-13.23,-186.24) v1(-13.23,-187) v1(-13.23,-187.76) v1(-13.23,-188.52) v1(-13.23,-189.28) v2(-22.61,-169.55) v2(-22.61,-170.81) v2(-22.61,-172.09) v2(-22.61,-173.35) v2(-22.61,-174.62) v2(-22.61,-175.9) v2(-22.61,-177.16) v2(-22.61,-178.44) v2(-22.61,-179.71) v2(-22.61,-180.97) v2(-22.61,-182.25) v2(-22.55,-160.68) v2(-22.52,-165.39) v2(-22.52,-165.79) v2(-22.52,-166.2) v2(-22.52,-166.6) v2(-22.52,-167.01) v2(-22.52,-167.42) v2(-22.52,-167.82) v2(-22.52,-168.23) v2(-22.19,-154.55) v2(-22.19,-155.56) v2(-22.19,-156.52) v2(-22.19,-157.53) v2(-22.19,-158.55) v2(-22.19,-159.57) v2(-22.11,-165.39) v2(-22.11,-165.79) v2(-22.11,-166.2) v2(-22.11,-166.6) v2(-22.11,-167.01) v2(-22.11,-167.42) v2(-22.11,-167.82) v2(-22.11,-168.23) v2(-21.71,-165.39) v2(-21.71,-165.79) v2(-21.71,-166.2) v2(-21.71,-166.6) v2(-21.71,-167.01) v2(-21.71,-167.42) v2(-21.71,-167.82) v2(-21.71,-168.23) v2(-21.59,-168.91) v2(-21.59,-170.18) v2(-21.59,-171.45) v2(-21.59,-172.72) v2(-21.59,-173.99) v2(-21.59,-175.26) v2(-21.59,-176.53) v2(-21.59,-177.8) v2(-21.59,-179.07) v2(-21.59,-180.34) v2(-21.59,-181.61) v2(-21.3,-165.39) v2(-21.3,-165.79) v2(-21.3,-166.2) v2(-21.3,-166.6) v2(-21.3,-167.01) v2(-21.3,-167.42) v2(-21.3,-167.82) v2(-21.3,-168.23) v2(-21.11,-154.55) v2(-21.11,-155.56) v2(-21.11,-156.52) v2(-21.11,-157.53) v2(-21.11,-158.55) v2(-21.11,-159.57) v2(-21.11,-160.58) v2(-20.89,-165.39) v2(-20.89,-165.79) v2(-20.89,-166.2) v2(-20.89,-166.6) v2(-20.89,-167.01) v2(-20.89,-167.42) v2(-20.89,-167.82) v2(-20.89,-168.23) v2(-20.49,-165.39) v2(-20.49,-165.79) v2(-20.49,-166.2) v2(-20.49,-166.6) v2(-20.49,-167.01) v2(-20.49,-167.42) v2(-20.49,-167.82) v2(-20.49,-168.23) v2(-20.32,-168.91) v2(-20.32,-170.18) v2(-20.32,-171.45) v2(-20.32,-172.72) v2(-20.32,-173.99) v2(-20.32,-175.26) v2(-20.32,-176.53) v2(-20.32,-177.8) v2(-20.32,-179.07) v2(-20.32,-180.34) v2(-20.32,-181.61) v2(-20.32,-182.88) v2(-20.32,-184.15) v2(-20.32,-185.42) v2(-20.08,-165.39) v2(-20.08,-165.79) v2(-20.08,-166.2) v2(-20.08,-166.6) v2(-20.08,-167.01) v2(-20.08,-167.42) v2(-20.08,-167.82) v2(-20.08,-168.23) v2(-19.9,-158.55) v2(-19.9,-159.57) v2(-19.9,-160.58) v2(-19.68,-165.39) v2(-19.68,-165.79) v2(-19.68,-166.2) v2(-19.68,-166.6) v2(-19.68,-167.01) v2(-19.68,-167.42) v2(-19.68,-167.82) v2(-19.68,-168.23) v2(-19.09,-169.57) v2(-19.09,-170.59) v2(-19.09,-171.61) v2(-19.09,-172.62) v2(-19.09,-173.68) v2(-19.09,-174.7) v2(-19.09,-175.71) v2(-19.09,-178.04) v2(-19.09,-179.06) v2(-19.09,-180.07) v2(-19.09,-181.09) v2(-19.09,-182.11) v2(-19.09,-183.12) v2(-19.09,-184.14) v2(-19.09,-185.15) v2(-19.09,-186.17) v2(-19.09,-187.19) v2(-19.09,-188.2) v2(-19.09,-189.22) v2(-19.01,-158.55) v2(-19.01,-159.57) v2(-19.01,-160.58) v2(-19.08,-168.58) v2(-19.08,-176.76) v2(-19.08,-177.45) v2(-18.12,-154.55) v2(-18.12,-155.56) v2(-18.1,-156.49) v2(-18.1,-157.5) v2(-18.1,-158.52) v2(-18.1,-159.54) v2(-18.1,-160.55) v2(-18.18,-165.41) v2(-18.18,-165.82) v2(-18.18,-166.22) v2(-18.18,-166.63) v2(-18.18,-167.04) v2(-17.93,-177.09) v2(-17.77,-165.41) v2(-17.77,-165.82) v2(-17.77,-166.22) v2(-17.77,-166.63) v2(-17.77,-167.04) v2(-17.36,-165.41) v2(-17.36,-165.82) v2(-17.36,-166.22) v2(-17.36,-166.63) v2(-17.36,-167.04) v2(-16.96,-165.41) v2(-16.96,-165.82) v2(-16.96,-166.22) v2(-16.96,-166.63) v2(-16.96,-167.04) v2(-16.79,-176.74) v2(-16.79,-177.45) v2(-16.78,-170.51) v2(-16.78,-171.52) v2(-16.78,-172.67) v2(-16.78,-173.68) v2(-16.78,-174.7) v2(-16.78,-175.71) v2(-16.78,-178.13) v2(-16.78,-179.06) v2(-16.78,-180.07) v2(-16.78,-181.09) v2(-16.78,-182.11) v2(-16.78,-183.12) v2(-16.78,-184.14) v2(-16.78,-185.15) v2(-16.78,-186.17) v2(-16.78,-187.19) v2(-16.78,-188.2) v2(-16.78,-189.22) v2(-16.55,-165.41) v2(-16.55,-165.82) v2(-16.55,-166.22) v2(-16.55,-166.63) v2(-16.55,-167.04) v2(-16.14,-165.41) v2(-16.14,-165.82) v2(-16.14,-166.22) v2(-16.14,-166.63) v2(-16.14,-167.04) v2(-15.82,-154.46) v2(-15.82,-155.47) v2(-15.82,-156.49) v2(-15.82,-157.5) v2(-15.82,-158.52) v2(-15.82,-159.54) v2(-15.82,-160.55) v2(-15.82,-161.57) v2(-15.82,-162.58) v2(-15.74,-165.41) v2(-15.74,-165.82) v2(-15.74,-166.22) v2(-15.74,-166.63) v2(-15.74,-167.04) v2(-15.77,-171.12) v2(-15.65,-183.19) v2(-15.62,-184.15) v2(-15.65,-185.22) v2(-15.39,-175.57) v2(-15.39,-176.33) v2(-15.39,-177.09) v2(-15.39,-177.73) v2(-15.27,-170.61) v2(-15.24,-171.45) v2(-15.24,-172.72) v2(-15.08,-163.61) v2(-15.08,-164.01) v2(-15.08,-164.42) v2(-14.82,-158.49) v2(-14.82,-159.57) v2(-14.82,-160.58) v2(-14.82,-161.6) v2(-14.82,-162.61) v2(-14.67,-163.61) v2(-14.67,-164.01) v2(-14.67,-164.42) v2(-14.67,-164.83) v2(-14.63,-183.19) v2(-14.63,-184.2) v2(-14.38,-171.76) v2(-14.27,-163.61) v2(-14.27,-164.01) v2(-14.27,-164.42) v2(-14.27,-164.83) v2(-14.27,-165.23) v2(-14.27,-165.64) v2(-14.27,-166.05) v2(-14.27,-166.45) v2(-14.27,-166.86) v2(-14.27,-167.27) v2(-14,-175.57) v2(-13.86,-163.61) v2(-13.86,-164.01) v2(-13.86,-164.42) v2(-13.86,-164.83) v2(-13.86,-165.23) v2(-13.86,-165.64) v2(-13.86,-166.05) v2(-13.86,-166.45) v2(-13.86,-166.86) v2(-13.86,-167.27) v2(-13.74,-158.55) v2(-13.74,-159.57) v2(-13.74,-160.58) v2(-13.74,-161.6) v2(-13.74,-162.61) v2(-13.61,-183.19) v2(-13.61,-184.2) v2(-13.45,-163.61) v2(-13.45,-164.01) v2(-13.45,-164.42) v2(-13.45,-164.83) v2(-13.45,-165.23) v2(-13.45,-165.64) v2(-13.45,-166.05) v2(-13.45,-166.45) v2(-13.45,-166.86) v2(-13.45,-167.27) v2(-13.05,-163.61) v2(-13.05,-164.01) v2(-13.05,-164.42) v2(-13.05,-164.83) v2(-13.05,-165.23) v2(-13.05,-165.64) v2(-13.05,-166.05) v2(-13.05,-166.45) v2(-13.05,-166.86) v2(-13.05,-167.27) v2(-12.85,-176.33) v2(-12.85,-177.22) v2(-12.85,-177.85) v2(-12.66,-154.55) v2(-12.66,-155.56) v2(-12.66,-156.58) v2(-12.66,-157.6) v2(-12.66,-158.55) v2(-12.66,-159.57) v2(-12.66,-160.58) v2(-12.66,-161.6) v2(-12.66,-162.61) v2(-12.64,-163.61) v2(-12.64,-164.01) v2(-12.64,-164.42) v2(-12.64,-164.83) v2(-12.64,-165.23) v2(-12.64,-165.64) v2(-12.64,-166.05) v2(-12.64,-166.45) v2(-12.64,-166.86) v2(-12.64,-167.27) v2(-12.6,-175.57) v2(-12.23,-163.61) v2(-12.23,-164.01) v2(-12.23,-164.42) v2(-12.23,-164.83) v2(-12.23,-165.23) v2(-12.23,-165.64) v2(-12.23,-166.05) v2(-12.23,-166.45) v2(-12.23,-166.86) v2(-12.23,-167.27) v2(-11.83,-163.61) v2(-11.83,-164.01) v2(-11.83,-164.42) v2(-11.83,-164.83) v2(-11.83,-165.23) v2(-11.83,-165.64) v2(-11.83,-166.05) v2(-11.83,-166.45) v2(-11.83,-166.86) v2(-11.83,-167.27) v2(-11.65,-154.55) v2(-11.65,-155.56) v2(-11.65,-156.58) v2(-11.65,-157.6) v2(-11.65,-158.55) v2(-11.65,-159.57) v2(-11.65,-160.58) v2(-11.65,-161.6) v2(-11.65,-162.61) v2(-11.42,-163.61) v2(-11.42,-164.01) v2(-11.42,-164.42) v2(-11.42,-164.83) v2(-11.42,-165.23) v2(-11.42,-165.64) v2(-11.42,-166.05) v2(-11.42,-166.45) v2(-11.42,-166.86) v2(-11.42,-167.27) v2(-11.43,-189.23) v2(-11.01,-164.01) v2(-11.01,-164.42) v2(-11.01,-164.83) v2(-11.01,-165.23) v2(-11.01,-165.64) v2(-11.01,-166.05) v2(-11.01,-166.45) v2(-11.01,-166.86) v2(-11.01,-167.27) v2(-10.63,-154.55) v2(-10.63,-155.56) v2(-10.63,-156.58) v2(-10.63,-157.6) v2(-10.63,-158.55) v2(-10.63,-159.57) v2(-10.63,-160.58) v2(-10.63,-161.6) v2(-10.63,-162.61) v2(-10.19,-163.76) v2(-10.16,-165.1) v2(-10.16,-166.37) v2(-10.16,-167.64) v2(-10.16,-168.91) v2(-10.16,-170.18) v2(-10.16,-171.45) v2(-10.16,-172.72) v2(-10.16,-189.23) v2(-9.61,-154.55) v2(-9.61,-155.56) v2(-9.61,-156.58) v2(-9.61,-157.6) v2(-9.61,-158.55) v2(-9.61,-159.57) v2(-9.61,-160.58) v2(-9.61,-161.6) v2(-9.61,-162.61) v2(-8.89,-163.77) v2(-8.89,-165.04) v2(-8.89,-166.37) v2(-8.89,-167.64) v2(-8.89,-168.91) v2(-8.89,-170.18) v2(-8.89,-171.45) v2(-8.89,-187.96) v2(-8.89,-189.23) v2(-8.66,-156.58) v2(-8.66,-157.6) v2(-8.66,-158.55) v2(-8.66,-159.57) v2(-8.66,-160.58) v2(-8.66,-161.6) v2(-8.66,-162.61) v2(-7.62,-167.64) v2(-7.62,-168.91) v2(-7.62,-187.96) v2(-7.62,-189.23) v2(-7.14,-181.54) v2(-7.14,-182.3) v2(-7.14,-183.19) v2(-6.35,-187.96) v2(-6.35,-189.23) v2(-6.12,-181.54) v2(-6.12,-182.3) v2(-6.12,-183.19) v2(-6.04,-168.68) v2(-6.04,-169.19) v2(-6.04,-169.7) v2(-5.53,-169.19) v2(-5.53,-169.7) v2(-5.02,-169.19) v2(-5.02,-169.7) v2(-5.08,-175.26) v2(-5.08,-176.53) v2(-5.08,-177.8) v2(-5.08,-179.07) v2(-5.08,-180.34) v2(-5.08,-181.61) v2(-5.08,-182.88) v2(-5.08,-186.69) v2(-5.08,-187.96) v2(-5.08,-189.23) v2(-4.51,-169.19) v2(-4.51,-169.7) v2(-4.51,-170.2) v2(-3.81,-176.53) v2(-3.81,-177.8) v2(-3.81,-179.07) v2(-3.81,-180.34) v2(-3.81,-181.61) v2(-3.81,-182.88) v2(-3.81,-185.67) v2(-3.81,-186.69) v2(-3.81,-187.96) v2(-3.81,-189.23) v2(-2.99,-170.46) v2(-2.99,-171.09) v2(-2.54,-176.53) v2(-2.54,-177.8) v2(-2.54,-179.07) v2(-2.54,-180.34) v2(-2.54,-181.61) v2(-2.54,-182.88) v2(-2.57,-183.95) v2(-2.54,-185.67) v2(-2.54,-186.69) v2(-2.54,-187.96) v2(-2.54,-189.23) v2(-2.36,-170.46) v2(-2.36,-171.09) v2(-1.27,-176.53) v2(-1.27,-177.8) v2(-1.27,-179.07) v2(-1.27,-180.34) v2(-1.27,-181.61) v2(-1.27,-182.88) v2(-1.27,-184.15) v2(-1.27,-185.42) v2(-1.27,-186.69) v2(-1.27,-187.96) v2(-1.27,-189.23) v2(0,-175.26) v2(0,-176.53) v2(0,-177.8) v2(0,-179.07) v2(0,-180.34) v2(0,-181.61) v2(0,-185.42) v2(0,-186.69) v2(0,-187.96) v2(0,-189.23)
PGND: length 3.9
  BOTTOM w0.508: -3.96,-161.81 C2.1 ; C2.1 -5.12,-160.45 ; C2.1 -3.96,-159.09
  vias: v1(-7.01,-163.25) v1(-7.01,-164.26) v1(-6.88,-165.31) v1(-6.25,-164.14) v1(-6.25,-165.79) v1(-6.12,-163.25) v1(-6.12,-164.9) v1(-6.12,-166.55) v1(-5.74,-156.77) v1(-5.74,-167.19) v1(-5.61,-161.09) v1(-5.49,-158.93) v1(-5.49,-165.71) v1(-5.33,-162.05) v1(-4.86,-166.3) v1(-4.8,-167.9) v1(-4.57,-162.05) v1(-4.41,-156.51) v1(-4.45,-165.28) v1(-4.34,-158.93) v1(-3.7,-165.3) v1(-2.32,-166.81)
UNNAMED_7_ADL5606_I18_RFIN: length 4.6
  TOP w0.305: -17.93,-172.62 C1.2
  TOP w0.356: A1.1 -17.93,-169.15
  TOP w0.635: -17.93,-172.62 CIN.2 -17.93,-169.15
UNNAMED_7_ADL5606_I18_RFOUT1: length 6.1
  TOP w0.457: C8.1 -16.96,-160.36 -16.96,-160.36
  TOP w0.635: A1.11 A1.10 A1.9 ; A1.11 -16.96,-163.97 L2.1 -16.96,-161.35 COUT.2 -16.96,-160.36 ; A1.11 A1.12
UNNAMED_7_CAP_I76_N2: length 3.7
  TOP w0.457: -16.96,-159.32 C8.2
  TOP w0.635: J2.1 -16.96,-155.67 -16.96,-159.32
UNNAMED_7_CAP_I108_N2: length 9.7
  TOP w0.305: R2.2 -9.37,-182.17 v1(-9.65,-181.89)
  BOTTOM w0.203: U1.B1 -10.89,-179.63 ; U1.B1 -10.89,-178.81 ; U1.B1 -11.71,-178.81 ; U1.B1 -11.71,-179.63 ; U1.A2 -9.62,-180.9 ; U1.A2 -10.44,-180.08 ; U1.A2 -10.44,-180.9 ; U1.A2 -9.62,-180.08 ; -11.71,-180.9 U1.A1 ; U1.A1 -10.89,-180.08 ; U1.A1 -11.71,-180.08 ; U1.A1 -10.89,-180.9 ; -10.44,-178.81 U1.B2 ; U1.B2 -10.44,-179.63 ; U1.B2 -9.62,-179.63
UNNAMED_7_CAP_I113_N2: length 9.2
  BOTTOM w0.305: U1.H4 -7.08,-171.19 ; U1.H4 -6.86,-172.24 ; U1.H4 -7.5,-171.6 -8.12,-172.22 ; -5.81,-172.46 U1.G5 -6.86,-172.24 ; U1.G3 -8.76,-172.86 -8.12,-172.22 ; -6.86,-172.24 U1.H5 ; -6.86,-172.24 U1.G4 -7.49,-172.85 -8.12,-172.22 ; -6.63,-171.19 U1.H5 ; U1.H5 -5.81,-172.01 ; U1.H5 -5.81,-171.19
  vias: v1(-5.18,-171.56) v1(-5.17,-172.31) v1(-5.18,-173.06) v1(-4.64,-173.63) v1(-4.06,-172.34) v1(-2.92,-172.34) v1(-2.36,-173.63) v1(-1.65,-172.34) v1(-0.76,-170.69) v1(-0.76,-171.45) v1(-0.57,-172.28) v1(0.25,-172.97) v1(0.31,-173.76) v1(0.44,-172.09)
UNNAMED_7_CAP_I120_N2: length 3.9
  BOTTOM w0.508: C2.2 -2.32,-160.45 ; C2.2 -1.17,-161.81 ; C2.2 -1.17,-159.09
UNNAMED_7_CAP_I132_N2: length 3.4
  BOTTOM w0.305: C9.2 C6.2 U1.F1
UNNAMED_7_CN5P3SHLD_I127_N6: length 15.2
  BOTTOM w0.305: P1.SH1 -7.77,-155.21 -7.77,-155.76 -7.39,-155.76 -7.06,-156.08 -5.4,-156.08 -4.31,-154.99 P1.SH2 -3.31,-154.99 -2.22,-156.08 -0.72,-156.08 P1.SH3
  BOTTOM w0.762: -7.77,-155.76 -7.14,-156.39 -7.14,-159.63 R1.2
UNNAMED_7_DIOLED_I150_P: length 1.6
  BOTTOM w0.508: DS1.A R4.1
UNNAMED_7_FERRITE_I107_N1: length 2.2
  TOP w0.305: R3.2 -9.37,-185.22 v1(-8.51,-186.08)
UNNAMED_7_LINLTM8045_I104_FB: length 4
  TOP w0.305: R3.1 R2.1 -8.38,-182.75 v1(-8.38,-181.64)
  BOTTOM w0.305: U1.A3 -8.76,-181.25 v1(-8.38,-181.64)
UNNAMED_7_LINLTM8045_I104_RT: length 2.3
  BOTTOM w0.305: RT.1 -12.35,-172.53 -12.01,-172.87 U1.G1

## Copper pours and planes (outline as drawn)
5V on TOP: -16.82,-167.97 -11.06,-167.97 -11.06,-169.93 -15.45,-169.93 -15.45,-169.93 -16.03,-169.93 -16.03,-169.35 -16.82,-168.56
5V on TOP: -22.86,-164.56 -22.86,-161.42 -18.77,-161.42 -18.04,-162.15 -18.04,-163.46 -18.67,-163.46 -19.77,-164.55
5V on BOTTOM: -11.84,-186.29 -10.06,-186.29 -10.06,-188.07 -11.84,-188.07
5V on L3_PWR: -22.86,-189.87 -22.86,-161.6 -18.19,-161.6 -14.5,-165.28 -14.5,-167.69 -10.69,-167.69 -10.69,-170.49 -11.58,-170.49 -11.58,-182.88 -10.57,-183.9 -10.57,-189.87
GND on TOP (solid shape): -16.71,-177.47 -19.12,-177.47 -19.12,-176.71 -16.71,-176.71
GND on TOP: -23.01,-190.5 -23.01,-184.84 -22.86,-184.84 -22.86,-165.08 -18.14,-165.08 -18.14,-165.05 -15.29,-165.05 -15.29,-163.63 -16.12,-162.8 -16.12,-153.54 -11.38,-153.54 -11.38,-154.14 -8.15,-154.14 -8.15,-166.26 -5.45,-168.96 -1.97,-168.96 -1.97,-171.43 -4,-171.43 -4.69,-170.74 -5.99,-170.74 -5.99,-173.41 -4.67,-174.73 1.27,-174.73 1.27,-189.87 -12.41,-189.87 -12.41,-190.5 ; 2 cut-outs
GND on TOP: -22.86,-161.09 -22.86,-153.54 -17.8,-153.54 -17.8,-161.09
GND on BOTTOM: -22.86,-190.5 -22.86,-153.54 -11.38,-153.54 -11.38,-154.14 -8.92,-154.14 -8.92,-156.26 -8.15,-156.26 -8.15,-166.25 -5.65,-168.76 1.27,-168.76 1.27,-189.87 -12.41,-189.84 -12.41,-190.5 ; 1 cut-out
GND on L2_GND: -22.86,-190.5 -22.86,-153.54 -11.38,-153.54 -11.38,-154.17 1.27,-154.18 1.27,-189.87 -12.41,-189.87 -12.41,-190.5 ; 1 cut-out
GND on L3_PWR: -11.07,-189.79 -11.07,-171.25 -10.06,-171.25 -10.06,-167.19 -14,-167.19 -14,-165.15 -18.06,-161.09 -22.86,-161.09 -22.86,-154.14 -8.28,-154.14 -8.28,-166.17 -6.53,-167.92 1.29,-167.92 1.27,-189.79
PGND on TOP: -7.52,-154.16 1.27,-154.16 1.27,-169.65 -1.35,-169.65 -1.35,-168.33 -5.18,-168.33 -7.52,-165.99
PGND on BOTTOM: -5.18,-168.33 -7.52,-165.99 -7.52,-160.96 -6.88,-160.33 -6.88,-156.24 -3.2,-156.24 -3.2,-165.23 -1.98,-166.45 -1.98,-168.33
PGND on L2_GND: -7.52,-154.16 1.27,-154.16 1.27,-169.65 -1.35,-169.65 -1.35,-168.33 -1.98,-168.33 -5.18,-168.33 -7.52,-165.99
PGND on L3_PWR: -7.52,-154.16 1.27,-154.16 1.27,-169.65 -1.35,-169.65 -1.35,-168.33 -1.98,-168.33 -5.18,-168.33 -7.52,-165.99
UNNAMED_7_CAP_I108_N2 on BOTTOM: -15.24,-178.69 -10.29,-178.69 -9.27,-179.7 -9.27,-183.5 -10.53,-183.5 -12.01,-182.02 -15.24,-182.02
UNNAMED_7_CAP_I113_N2 on TOP: -5.49,-173.28 -4.68,-174.09 1.27,-174.09 1.27,-170.31 -1.35,-170.31 -1.35,-172.03 -4.06,-172.03 -4.83,-171.27 -5.49,-171.27
UNNAMED_7_CAP_I113_N2 on BOTTOM: -8.81,-172.88 -8.53,-173.16 -5.56,-173.15 -4.62,-174.09 1.27,-174.09 1.27,-168.86 -1.35,-168.86 -1.35,-172.03 -4.05,-172.03 -5.22,-170.87 -7.22,-170.87 -8.81,-172.46
UNNAMED_7_CAP_I120_N2 on BOTTOM: -1.3,-168.33 -1.3,-166.17 -2.57,-164.9 -2.57,-158.48 -2.69,-158.48 -2.69,-156.24 1.27,-156.24 1.27,-168.33
UNNAMED_7_FERRITE_I107_N1 on BOTTOM: -9.34,-187.18 -9.34,-185.53 -10.48,-185.53 -10.48,-184.13 -6.42,-184.13 -6.42,-187.18

Small or netless copper shapes (teardrops, artwork): 2 on TOP

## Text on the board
Ref Des/Silkscreen Bottom: WARNING: HOT SURFACE | 08-046520 REV B Z | SECONDARY SIDE
User.Comments: SEE DETAIL A | VIEWED FROM THE | PRIMARY SIDE | SCALE: NONE | DETAIL A | 5.    PARTS INDICATED BELOW SHOULD BE MOUNTED MANUALLY: | B.    J2, E028678, CONN-PCB EDGE SMA SMALL VERSION, CON-SMA-EDGE-S | A.    J1, E033180, CONN-PCB RCPT PLUG SMA END LAUNCH, 132365-10
Ref Des/Silkscreen Top: WARNING: HOT SURFACE | 08-046520 REV B Z | PRIMARY SIDE | EVAL-CN0417-EBZ
DIMENSION: SEE DETAIL A | BOARD DIMENSIONS | ARRAY DRAWING | (REF) | NON-PLATED: +/- 2 MILS | DIA MAX | SEE NOTE 14
PAGE_OUTLINE: B | AS PER ECR-077197, ECR-077830, AND ECR-079975 | 25JUL18 | T.CABILDO | CUSTOMER EVAL BOARD Z | PRIMARY SIDE
User.15: .028" | .01344" | 50 OHMS
User.17: 08-      -07 | L2 GND
User.18: L3 PWR | 08-      -08
User.45: FIGURE | SIZE | 8.0 | 8.01 | 10.0 | 10.01 | 25.0 | 125.0 | 34.0x26.0 | 51.0x24.0 | PLATED | NON-PLATED | FINISHED HOLES IN MILS | ALL UNITS ARE IN MILS | QTY | 426 | 73 | 48 | 59 | 96 | 4 | 2 | TOLERANCE/NOTES
